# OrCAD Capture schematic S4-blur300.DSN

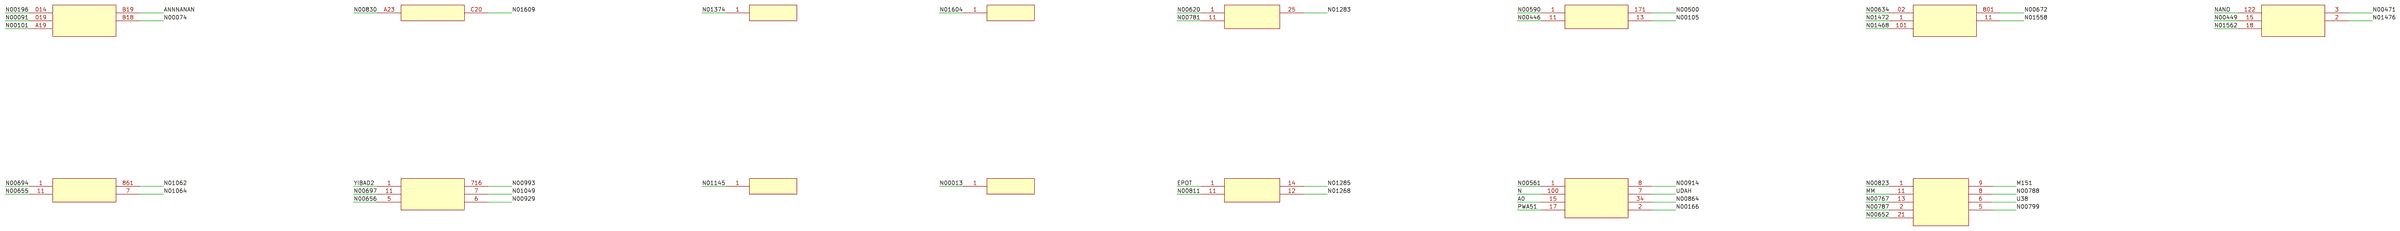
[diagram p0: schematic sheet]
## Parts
P1  CONNECTOR
P2  CONNECTOR
R20  510R
U19  74F02
U25  74F240
U27  74F174
U28  74F174
U29  74F174
U33  74F240
U34  74F240
U39  74F00
U40  74F10
U_1  74F240
U_2  AM291C
U_3  74F151

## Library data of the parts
P1 = OBS_P1
P2 = OBS_P2
R20 = OBS_R20
U19 = OBS_U19
U25 = OBS_U25
U27 = OBS_U27
U28 = OBS_U28
U29 = OBS_U29
U33 = OBS_U33
U34 = OBS_U34
U39 = OBS_U39
U40 = OBS_U40
U_1 = OBS_U_1
U_2 = OBS_U_2
U_3 = OBS_U_3

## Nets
A0: U_2.15
ANNNANAN: P1.B19
EPOT: U_1.1
M151: U_3.9
MM: U_3.11
N: U_2.100
NANO: U29.122
PWA51: U_2.17
U38: U_3.6
UDAH: U_2.7
YIBAD2: U34.1

Not connected (* = marked no-connect by the designer): P1 014 019 A19 B18; P2 A23 C20; R20 1; U19 1; U25 1 11 25; U27 1 11 13 171; U28 1 02 11 101 801; U29 2 3 15 18; U33 1 7 11 861; U34 5 6 7 11 716; U39 1; U40 1; U_1 11 12 14; U_2 1 2 8 34; U_3 1 2 5 8 13 21
